VERSION 5.7 ;
DIVIDERCHAR "/" ;
BUSBITCHARS "[]" ;

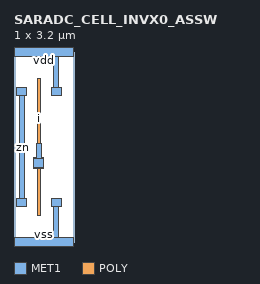
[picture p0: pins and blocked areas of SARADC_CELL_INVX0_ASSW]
MACRO SARADC_CELL_INVX0_ASSW
  CLASS BLOCK ;
  FOREIGN SARADC_CELL_INVX0_ASSW ;
  ORIGIN 0.000 0.000 ;
  SIZE 1.000 BY 3.200 ;
  SYMMETRY X Y R90 ;
  PIN vnw
  END vnw
  PIN vpw
  END vpw
  PIN vdd
    DIRECTION INOUT ;
    USE POWER ;
    PORT
      LAYER MET1 ;
        RECT 0.625 2.470 0.795 2.610 ;
        RECT 0.665 2.610 0.755 3.120 ;
        RECT 0.000 3.120 1.000 3.280 ;
    END
  END vdd
  PIN vss
    DIRECTION INOUT ;
    USE GROUND ;
    PORT
      LAYER MET1 ;
        RECT 0.000 -0.080 1.000 0.080 ;
        RECT 0.665 0.080 0.755 0.590 ;
        RECT 0.625 0.590 0.795 0.730 ;
    END
  END vss
  PIN i
    DIRECTION INPUT ;
    USE SIGNAL ;
    ANTENNAGATEAREA 0.030000 ;
    PORT
      LAYER POLY ;
        RECT 0.390 0.445 0.450 1.245 ;
        RECT 0.335 1.245 0.505 1.415 ;
        RECT 0.390 1.415 0.450 2.755 ;
      LAYER MET1 ;
        RECT 0.335 1.260 0.505 1.400 ;
        RECT 0.375 1.400 0.465 1.665 ;
    END
  END i
  PIN zn
    DIRECTION INOUT ;
    USE POWER ;
    PORT
      LAYER MET1 ;
        RECT 0.045 0.590 0.215 0.730 ;
        RECT 0.085 0.730 0.175 2.470 ;
        RECT 0.045 2.470 0.215 2.610 ;
    END
  END zn
END SARADC_CELL_INVX0_ASSW

END LIBRARY
